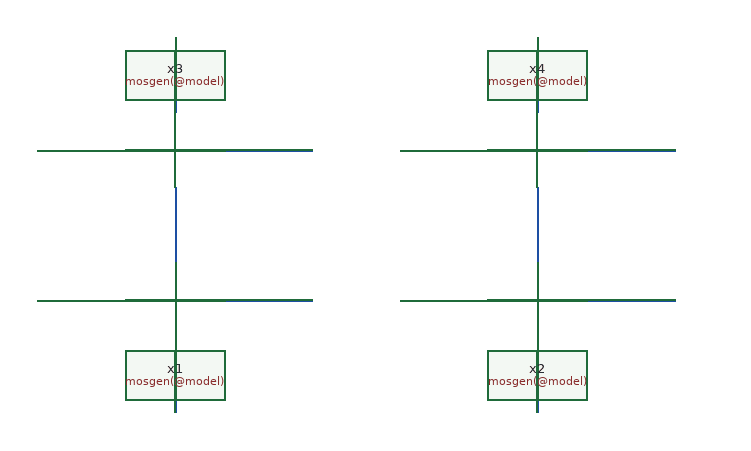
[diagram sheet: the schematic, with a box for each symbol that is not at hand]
v {xschem version=3.1.0 file_version=1.2
}
G {}
K {}
V {}
S {}
E {}
N 500 -140 610 -140 {
lab=#net1}
N 500 -230 500 -170 {
lab=#net2}
N 390 -140 460 -140 {
lab=#net3}
N 500 -110 500 -50 {
lab=#net4}
N 790 -140 900 -140 {
lab=#net5}
N 790 -230 790 -170 {
lab=#net6}
N 680 -140 750 -140 {
lab=#net7}
N 790 -110 790 -50 {
lab=#net8}
N 500 -260 610 -260 {
lab=#net9}
N 390 -260 460 -260 {
lab=#net10}
N 790 -260 900 -260 {
lab=#net11}
N 680 -260 750 -260 {
lab=#net12}
N 500 -350 500 -290 {
lab=#net13}
N 790 -350 790 -290 {
lab=#net14}
C {mosgen(@model)} 480 -140 0 0 {name=x1
model=nfet_01v8}
C {mosgen(@model)} 770 -140 0 0 {name=x2
model=nfet_g5v0d10v5}
C {mosgen(@model)} 480 -260 0 0 {name=x3
model=pfet_01v8}
C {mosgen(@model)} 770 -260 0 0 {name=x4
model=pfet_g5v0d10v5}
